One B-rep face of a CAD part: STEP entity #177.
In plain terms, the planar face has unit normal (1, 0, 0).
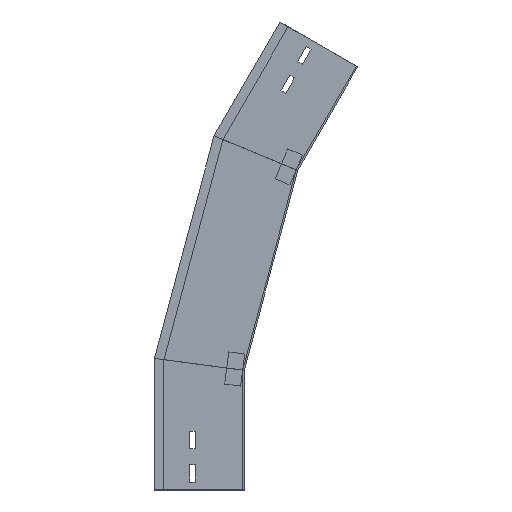
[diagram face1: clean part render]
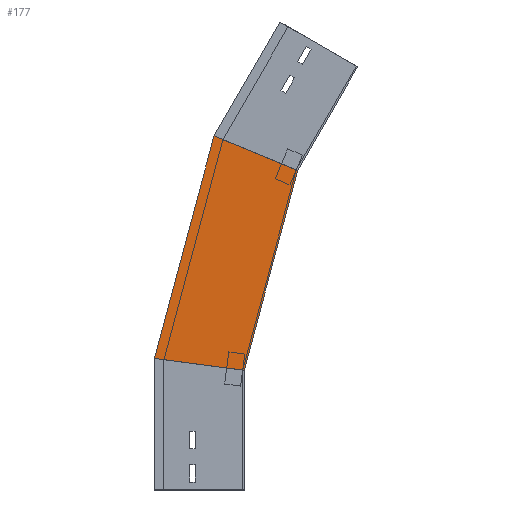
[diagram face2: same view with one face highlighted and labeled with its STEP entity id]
Its self-contained STEP definition (entity closure, numbers rounded to 3 decimals):
#63 = VECTOR ( 'NONE', #1385, 1000. ) ;
#126 = LINE ( 'NONE', #460, #63 ) ;
#177 = ADVANCED_FACE ( 'NONE', ( #928 ), #699, .T. ) ;
#187 = CARTESIAN_POINT ( 'NONE',  ( 0., 0., 150. ) ) ;
#222 = ORIENTED_EDGE ( 'NONE', *, *, #767, .F. ) ;
#424 = CARTESIAN_POINT ( 'NONE',  ( 0., 4.243, 134.167 ) ) ;
#442 = DIRECTION ( 'NONE',  ( 0., -0.259, 0.966 ) ) ;
#446 = CARTESIAN_POINT ( 'NONE',  ( 0., 37.799, 443.598 ) ) ;
#460 = CARTESIAN_POINT ( 'NONE',  ( 0., -100.244, 386.419 ) ) ;
#550 = LINE ( 'NONE', #653, #640 ) ;
#553 = DIRECTION ( 'NONE',  ( 0., -0.259, 0.966 ) ) ;
#561 = EDGE_CURVE ( 'NONE', #862, #1191, #126, .T. ) ;
#577 = CARTESIAN_POINT ( 'NONE',  ( 0., 4.243, 134.167 ) ) ;
#640 = VECTOR ( 'NONE', #1456, 1000. ) ;
#653 = CARTESIAN_POINT ( 'NONE',  ( 0., -19.411, 147.444 ) ) ;
#675 = ORIENTED_EDGE ( 'NONE', *, *, #561, .T. ) ;
#679 = DIRECTION ( 'NONE',  ( 1., 0., 0. ) ) ;
#699 = PLANE ( 'NONE',  #1220 ) ;
#767 = EDGE_CURVE ( 'NONE', #1475, #1024, #550, .T. ) ;
#785 = DIRECTION ( 'NONE',  ( 0., 0., -1. ) ) ;
#862 = VERTEX_POINT ( 'NONE', #446 ) ;
#928 = FACE_OUTER_BOUND ( 'NONE', #1048, .T. ) ;
#944 = CARTESIAN_POINT ( 'NONE',  ( 0., 112.5, 164.811 ) ) ;
#957 = VECTOR ( 'NONE', #442, 1000. ) ;
#1024 = VERTEX_POINT ( 'NONE', #187 ) ;
#1040 = ORIENTED_EDGE ( 'NONE', *, *, #1321, .F. ) ;
#1048 = EDGE_LOOP ( 'NONE', ( #1136, #675, #1040, #222 ) ) ;
#1094 = CARTESIAN_POINT ( 'NONE',  ( 0., -67.034, 400.175 ) ) ;
#1136 = ORIENTED_EDGE ( 'NONE', *, *, #1459, .T. ) ;
#1191 = VERTEX_POINT ( 'NONE', #1094 ) ;
#1220 = AXIS2_PLACEMENT_3D ( 'NONE', #577, #679, #785 ) ;
#1321 = EDGE_CURVE ( 'NONE', #1024, #1191, #1471, .T. ) ;
#1358 = LINE ( 'NONE', #1479, #1463 ) ;
#1385 = DIRECTION ( 'NONE',  ( 0., -0.924, -0.383 ) ) ;
#1456 = DIRECTION ( 'NONE',  ( 0., -0.991, -0.131 ) ) ;
#1459 = EDGE_CURVE ( 'NONE', #1475, #862, #1358, .T. ) ;
#1463 = VECTOR ( 'NONE', #553, 1000. ) ;
#1471 = LINE ( 'NONE', #424, #957 ) ;
#1475 = VERTEX_POINT ( 'NONE', #944 ) ;
#1479 = CARTESIAN_POINT ( 'NONE',  ( 0., 112.909, 163.284 ) ) ;
